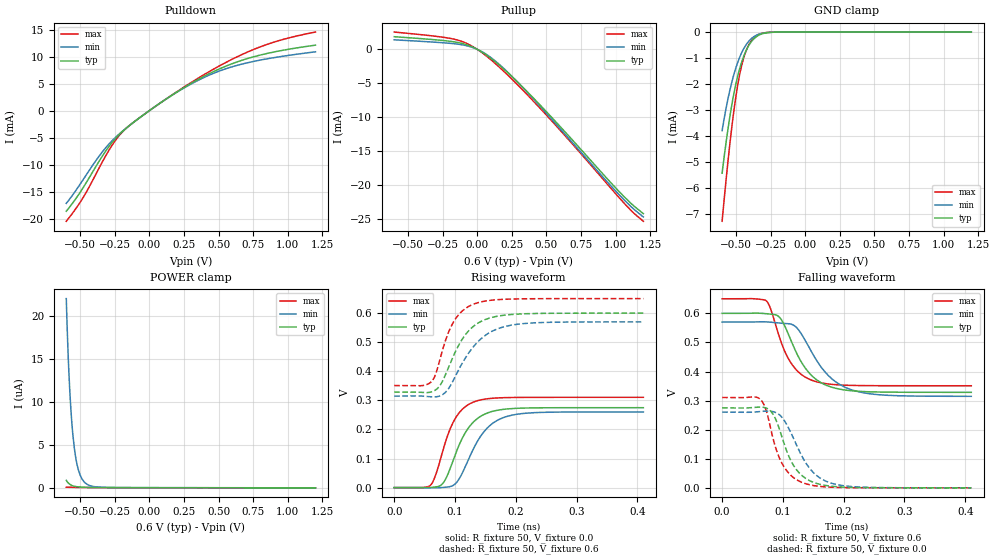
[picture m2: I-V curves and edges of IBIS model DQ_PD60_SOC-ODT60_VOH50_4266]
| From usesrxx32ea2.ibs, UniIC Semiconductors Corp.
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| DQ_PD60_SOC-ODT60_VOH50_4266
| (60 Ohm Pulldown, 60 Ohm System ODT Setting, VOH=VDDQ*0.50, 3200-4266Mbps)
[Model]   DQ_PD60_SOC-ODT60_VOH50_4266
Model_type   I/O
Vinl = 90.000mV
Vinh = 210.000mV
Vmeas = 150.000mV
Vref = 0.0mV
Cref = 0.0pF
Rref = 60.000Ohm
|   typ   min   max
|C_comp   0.834pF   0.784pF   0.884pF
C_comp_pullup   0.4170pF   0.3920pF   0.4420pF
C_comp_pulldown   0.4170pF   0.3920pF   0.4420pF
| Note: C_comp changes when the ODT circuit is enabled.
[Model Spec]
| Input threshold voltage corners
Vinl   0.0900V   0.0825V   0.1025V
Vinh   0.2100V   0.2025V   0.2225V
| Measurement voltage corners
Vmeas   0.1500V   0.1425V   0.1625V
| Timing spec test load voltage corners
Vref   0.0000V   0.0000V   0.0000V
| Dynamic Overshoot Parameters from LPDDR4_0P6 Specification
D_overshoot_ampl_h   0.30   NA   NA
D_overshoot_ampl_l   0.30   NA   NA
D_overshoot_area_h   0.1n   NA   NA
D_overshoot_area_l   0.1n   NA   NA
[Voltage Range]   0.6000V   0.5700V   0.6500V
[Pullup Reference]   0.6000V   0.5700V   0.6500V
| Junction Temperature (Ambient temp is 35C typ 95C min -40C max)
[Temperature Range]   50.0   110.0   -40.0
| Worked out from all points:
|   slope of the pulldown table from 0 to 0.09 V, typ, clamps not added: 55.7 ohm
|   slope of the pullup table from 0 to 0.09 V, typ, clamps not added: 75.7 ohm
|   GND clamp passes 1 mA (typ) near -0.45 V on its own axis
|   rising waveform, R_fixture 50, V_fixture 0.0: 20-80 % time 37.7ps typ, 42.2ps min, 32.6ps max; typ from 0 V to 0.275 V
|   falling waveform, R_fixture 50, V_fixture 0.6: 20-80 % time 43.5ps typ, 52.6ps min, 36.2ps max; typ from 0.6 V to 0.328 V
|   rising waveform, R_fixture 50, V_fixture 0.6: 20-80 % time 42.3ps typ, 50.4ps min, 32.9ps max; typ from 0.328 V to 0.6 V
|   falling waveform, R_fixture 50, V_fixture 0.0: 20-80 % time 34ps typ, 41.7ps min, 30.1ps max; typ from 0.275 V to 0 V
[Pulldown]
|   Voltage   I(typ)   I(min)   I(max)
-600mV    -18.62mA   -17.16mA   -20.48mA
-479.4mV  -14.31mA   -12.82mA   -16.14mA
-349.8mV  -8.833mA   -7.981mA   -9.987mA
-258mV    -5.562mA   -5.293mA   -5.98mA
-196.8mV  -3.935mA   -3.866mA   -4.014mA
-114mV    -2.168mA   -2.169mA   -2.139mA
211.8mV   3.655mA    3.602mA    3.717mA
490.8mV   7.545mA    7.184mA    8.063mA
658.2mV   9.231mA    8.542mA    10.26mA
825.6mV   10.44mA    9.472mA    12.04mA
1.006V    11.36mA    10.22mA    13.45mA
1.2V      12.12mA    10.89mA    14.55mA
[GND Clamp]
|   Voltage   I(typ)   I(min)   I(max)
-600mV    -5.439mA   -3.802mA   -7.294mA
-565.8mV  -4.041mA   -2.789mA   -5.405mA
-537mV    -3.03mA    -2.086mA   -3.984mA
-510mV    -2.24mA    -1.545mA   -2.838mA
-483mV    -1.605mA   -1.108mA   -1.913mA
-457.8mV  -1.142mA   -788.2uA   -1.267mA
-427.2mV  -721.7uA   -495.2uA   -731.4uA
-396.6mV  -430.3uA   -293.3uA   -396.7uA
-358.8mV  -204.8uA   -141.3uA   -167.1uA
-301.2mV  -53.74uA   -39.26uA   -35.2uA
-218.4mV  -5.224uA   -4.672uA   -2.177uA
1.2V      0A         0A         0A
[Pullup]
|   Voltage   I(typ)   I(min)   I(max)
-600mV    1.862mA    1.404mA    2.549mA
-297.6mV  1.399mA    1.043mA    1.916mA
-146.4mV  1.034mA    781.4uA    1.389mA
-27.6mV   277.3uA    226.3uA    350.3uA
28.2mV    -327uA     -281uA     -397uA
85.8mV    -1.126mA   -1.018mA   -1.31mA
201mV     -3.083mA   -2.993mA   -3.411mA
357.6mV   -6.168mA   -6.244mA   -6.596mA
615mV     -11.72mA   -12.05mA   -12.27mA
1.009V    -20.59mA   -21.06mA   -21.46mA
1.106V    -22.59mA   -23.05mA   -23.62mA
1.2V      -24.19mA   -24.67mA   -25.31mA
[POWER Clamp]
|   Voltage   I(typ)   I(min)   I(max)
-600mV    870.6nA    21.97uA    72.65nA
-589.2mV  630.1nA    16.59uA    68.66nA
-583.8mV  538.6nA    14.38uA    66.96nA
-576.6mV  440.3nA    11.88uA    64.76nA
-565.8mV  328nA      8.878uA    61.57nA
-551.4mV  228.5nA    6.002uA    57.54nA
-533.4mV  154.5nA    3.671uA    52.81nA
-513.6mV  108.8nA    2.145uA    47.98nA
-492mV    81.81nA    1.201uA    43.12nA
-454.2mV  59.07nA    454.9nA    35.59nA
-304.8mV  31.78nA    52.14nA    15.54nA
1.2V      0A         0A         0A
[Ramp]
|   typ   min   max
| 20% - 80%
dV/dt_r   164.90m/37.66p   156.14m/42.15p   186.33m/32.58p
dV/dt_f   162.96m/43.53p   153.17m/52.61p   179.39m/36.16p
| 25% - 75%
|dV/dt_r   137.42m/29.82p   130.12m/33.41p   155.27m/25.73p
|dV/dt_f   135.80m/34.45p   127.64m/41.67p   149.49m/28.54p
R_load = 50
[Rising Waveform]
R_fixture = 50
V_fixture = 0.0
|   Time   V(typ)   V(min)   V(max)
0s        128.2uV    112.5uV    62.99uV
60ps      528.7uV    -338.6uV   9.002mV
68ps      2.334mV    -607.4uV   42.24mV
80ps      14.5mV     625uV      126.7mV
98ps      99.64mV    8.971mV    228.6mV
114ps     178mV      58.56mV    273.2mV
132ps     229mV      140.4mV    295.6mV
159ps     260.7mV    216.3mV    306.9mV
196ps     272.2mV    250.2mV    310.1mV
410ps     275mV      260.3mV    310.6mV
[Falling Waveform]
R_fixture   = 50
V_fixture   = 0.6
V_fixture_min = 0.57
V_fixture_max = 0.65
|   Time   V(typ)   V(min)   V(max)
0s        600mV      570mV      650mV
73ps      598.8mV    570.6mV    642.3mV
80ps      597.2mV    569.6mV    614.3mV
94ps      587.4mV    566.5mV    519.9mV
110ps     523.5mV    564.2mV    440.6mV
126ps     448.9mV    542.6mV    397.5mV
149ps     382.7mV    460.7mV    368.8mV
182ps     345mV      372.4mV    355.5mV
223ps     332.1mV    331.1mV    351.8mV
410ps     328.4mV    314.7mV    351mV
[Rising Waveform]
R_fixture   = 50
V_fixture   = 0.6
V_fixture_min = 0.57
V_fixture_max = 0.65
|   Time   V(typ)   V(min)   V(max)
0s        328.4mV    314.6mV    351mV
61ps      329mV      312.3mV    363.9mV
68ps      335.8mV    312.2mV    389.1mV
77ps      356.7mV    316.9mV    454.5mV
96ps      446.2mV    363.9mV    563.7mV
114ps     516.8mV    435.2mV    611mV
132ps     557.4mV    488.8mV    632.1mV
161ps     585.5mV    537.8mV    644.7mV
201ps     596.6mV    561.4mV    649mV
410ps     600mV      570mV      650mV
[Falling Waveform]
R_fixture = 50
V_fixture = 0.0
|   Time   V(typ)   V(min)   V(max)
0s        275mV      260.4mV    310.6mV
64ps      277.7mV    262.7mV    302mV
73ps      274.1mV    263.9mV    263.2mV
82ps      258.5mV    262.8mV    184.7mV
97ps      184.6mV    245.9mV    90.47mV
113ps     94.29mV    190.2mV    43.21mV
132ps     41.15mV    106mV      18.21mV
157ps     14.23mV    39.92mV    5.926mV
192ps     3.451mV    9.939mV    1.328mV
410ps     188.9uV    197.1uV    88.71uV
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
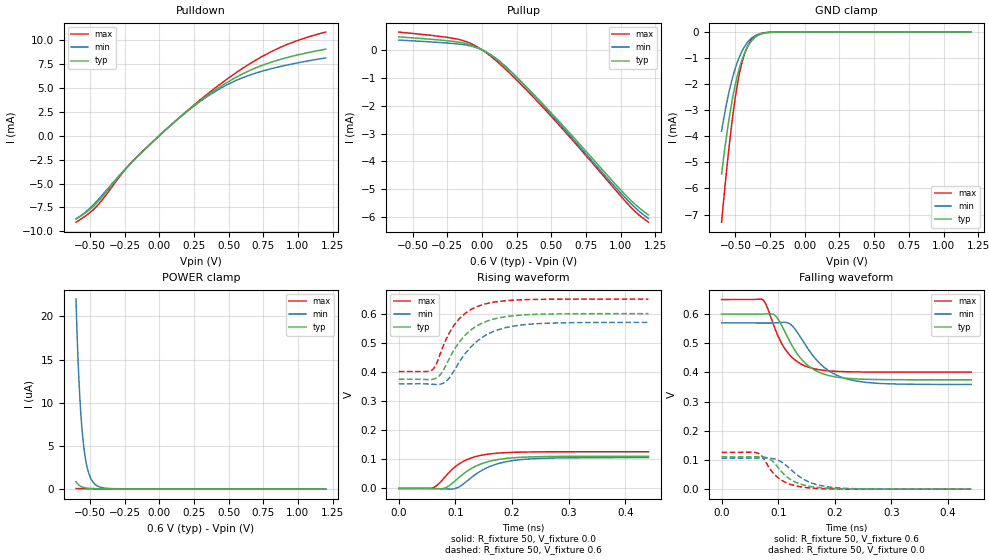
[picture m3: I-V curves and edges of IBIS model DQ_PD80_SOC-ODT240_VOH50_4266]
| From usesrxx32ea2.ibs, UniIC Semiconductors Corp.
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| DQ_PD80_SOC-ODT240_VOH50_4266
| (80 Ohm Pulldown, 240 Ohm System ODT Setting, VOH=VDDQ*0.50, 3200-4266Mbps)
[Model]   DQ_PD80_SOC-ODT240_VOH50_4266
Model_type   I/O
Vinl = 90.000mV
Vinh = 210.000mV
Vmeas = 150.000mV
Vref = 0.0mV
Cref = 0.0pF
Rref = 240.000Ohm
|   typ   min   max
|C_comp   0.834pF   0.784pF   0.884pF
C_comp_pullup   0.4170pF   0.3920pF   0.4420pF
C_comp_pulldown   0.4170pF   0.3920pF   0.4420pF
| Note: C_comp changes when the ODT circuit is enabled.
[Model Spec]
| Input threshold voltage corners
Vinl   0.0900V   0.0825V   0.1025V
Vinh   0.2100V   0.2025V   0.2225V
| Measurement voltage corners
Vmeas   0.1500V   0.1425V   0.1625V
| Timing spec test load voltage corners
Vref   0.0000V   0.0000V   0.0000V
| Dynamic Overshoot Parameters from LPDDR4_0P6 Specification
D_overshoot_ampl_h   0.30   NA   NA
D_overshoot_ampl_l   0.30   NA   NA
D_overshoot_area_h   0.1n   NA   NA
D_overshoot_area_l   0.1n   NA   NA
[Voltage Range]   0.6000V   0.5700V   0.6500V
[Pullup Reference]   0.6000V   0.5700V   0.6500V
| Junction Temperature (Ambient temp is 35C typ 95C min -40C max)
[Temperature Range]   50.0   110.0   -40.0
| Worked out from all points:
|   slope of the pulldown table from 0 to 0.09 V, typ, clamps not added: 75.6 ohm
|   slope of the pullup table from 0 to 0.09 V, typ, clamps not added: 306 ohm
|   GND clamp passes 1 mA (typ) near -0.45 V on its own axis
|   rising waveform, R_fixture 50, V_fixture 0.0: 20-80 % time 54.3ps typ, 56.9ps min, 47.6ps max; typ from 0 V to 0.11 V
|   falling waveform, R_fixture 50, V_fixture 0.6: 20-80 % time 47.3ps typ, 56.1ps min, 39.6ps max; typ from 0.6 V to 0.375 V
|   rising waveform, R_fixture 50, V_fixture 0.6: 20-80 % time 53ps typ, 58.6ps min, 45.8ps max; typ from 0.375 V to 0.6 V
|   falling waveform, R_fixture 50, V_fixture 0.0: 20-80 % time 38.7ps typ, 46.9ps min, 35.2ps max; typ from 0.111 V to 0 V
[Pulldown]
|   Voltage   I(typ)   I(min)   I(max)
-600mV    -8.692mA   -8.695mA   -9.046mA
-513.6mV  -7.87mA    -7.758mA   -8.201mA
-447mV    -6.974mA   -6.797mA   -7.322mA
-241.8mV  -3.459mA   -3.444mA   -3.485mA
-135.6mV  -1.874mA   -1.886mA   -1.844mA
130.8mV   1.709mA    1.698mA    1.715mA
247.8mV   3.122mA    3.073mA    3.178mA
370.2mV   4.454mA    4.329mA    4.624mA
577.2mV   6.292mA    5.923mA    6.818mA
800.4mV   7.658mA    6.983mA    8.741mA
967.8mV   8.348mA    7.534mA    9.805mA
1.2V      9.057mA    8.141mA    10.84mA
[GND Clamp]
|   Voltage   I(typ)   I(min)   I(max)
-600mV    -5.439mA   -3.802mA   -7.294mA
-565.8mV  -4.041mA   -2.788mA   -5.405mA
-535.2mV  -2.974mA   -2.045mA   -3.902mA
-508.2mV  -2.194mA   -1.512mA   -2.769mA
-483mV    -1.606mA   -1.109mA   -1.914mA
-456mV    -1.113mA   -769.6uA   -1.229mA
-427.2mV  -720.5uA   -496.7uA   -731.4uA
-398.4mV  -442.8uA   -303.7uA   -412uA
-360.6mV  -213.6uA   -146.5uA   -174.9uA
-303mV    -56.19uA   -40.92uA   -37.12uA
-202.2mV  -3.152uA   -2.988uA   -1.162uA
1.2V      0A         0A         0A
[Pullup]
|   Voltage   I(typ)   I(min)   I(max)
-600mV    465uA      350.7uA    636.6uA
-286.8mV  344.5uA    256.9uA    471.4uA
-139.2mV  251.1uA    190.4uA    336.1uA
-25.8mV   64.71uA    52.97uA    81.67uA
26.4mV    -75.59uA   -64.92uA   -91.9uA
82.2mV    -265.3uA   -239.4uA   -309.4uA
186.6mV   -696.9uA   -671.7uA   -775.1uA
307.2mV   -1.269mA   -1.271mA   -1.369mA
591.6mV   -2.763mA   -2.837mA   -2.897mA
978.6mV   -4.91mA    -5.02mA    -5.117mA
1.106V    -5.551mA   -5.669mA   -5.807mA
1.2V      -5.919mA   -6.049mA   -6.179mA
[POWER Clamp]
|   Voltage   I(typ)   I(min)   I(max)
-600mV    870.6nA    22uA       72.65nA
-589.2mV  630.2nA    16.59uA    68.66nA
-583.8mV  538.6nA    14.38uA    66.97nA
-576.6mV  439.2nA    11.87uA    64.76nA
-562.2mV  298.4nA    8.05uA     60.55nA
-547.8mV  211nA      5.442uA    56.57nA
-529.8mV  144.6nA    3.33uA     51.9nA
-506.4mV  97.9nA     1.762uA    46.31nA
-484.8mV  75.65nA    991.9nA    41.6nA
-450.6mV  57.67nA    416.8nA    34.94nA
-303mV    31.59nA    51.65nA    15.37nA
1.2V      0A         0A         0A
[Ramp]
|   typ   min   max
| 20% - 80%
dV/dt_r   66.28m/54.26p   63.59m/56.93p   75.63m/47.62p
dV/dt_f   135.04m/47.27p   126.64m/56.05p   149.25m/39.63p
| 25% - 75%
|dV/dt_r   55.23m/43.09p   52.99m/45.13p   63.03m/37.68p
|dV/dt_f   112.53m/37.46p   105.54m/44.39p   124.38m/31.36p
R_load = 50
[Rising Waveform]
R_fixture = 50
V_fixture = 0.0
|   Time   V(typ)   V(min)   V(max)
0s        20.21uV    7.273uV    14.24uV
58ps      -516.5uV   122.6uV    588.5uV
80ps      847uV      -1.599mV   36.07mV
98ps      23.63mV    -986uV     71.81mV
112ps     47.06mV    12.57mV    90.75mV
133ps     73.78mV    44.73mV    107.9mV
156ps     91.12mV    71.39mV    117.4mV
190ps     103.2mV    91.95mV    123.1mV
236ps     108.6mV    102mV      125.4mV
441ps     110.5mV    106mV      126.1mV
[Falling Waveform]
R_fixture   = 50
V_fixture   = 0.6
V_fixture_min = 0.57
V_fixture_max = 0.65
|   Time   V(typ)   V(min)   V(max)
0s        600mV      570mV      650mV
73ps      600.5mV    569.9mV    648.8mV
80ps      601.3mV    569.6mV    626.3mV
94ps      596.2mV    570.1mV    551.8mV
112ps     538.8mV    571.9mV    480.7mV
128ps     480.3mV    553mV      445.3mV
156ps     418.7mV    471.6mV    416.5mV
190ps     389.3mV    405mV      405.5mV
236ps     378.1mV    371.3mV    402mV
441ps     374.9mV    358.9mV    401.2mV
[Rising Waveform]
R_fixture   = 50
V_fixture   = 0.6
V_fixture_min = 0.57
V_fixture_max = 0.65
|   Time   V(typ)   V(min)   V(max)
0s        374.9mV    358.8mV    401.2mV
60ps      374.4mV    357mV      408.6mV
72ps      387.4mV    357.5mV    455.9mV
82ps      418.2mV    365.4mV    505.4mV
100ps     483.1mV    412.2mV    566.6mV
123ps     536.6mV    476.4mV    608.8mV
148ps     568.1mV    519.3mV    630.8mV
180ps     586.7mV    547.4mV    642.7mV
225ps     596.1mV    562.7mV    648.1mV
441ps     600mV      570mV      650mV
[Falling Waveform]
R_fixture = 50
V_fixture = 0.0
|   Time   V(typ)   V(min)   V(max)
0s        110.6mV    106.1mV    126.1mV
61ps      111.4mV    106.6mV    125.3mV
71ps      111.2mV    107mV      113.6mV
80ps      108mV      106.7mV    86.26mV
105ps     61.84mV    94.18mV    31.83mV
121ps     34.15mV    69.65mV    16.87mV
143ps     15.17mV    36.08mV    7.033mV
172ps     5.248mV    13.57mV    2.23mV
213ps     1.226mV    3.428mV    468.6uV
441ps     86.87uV    93.26uV    32.34uV
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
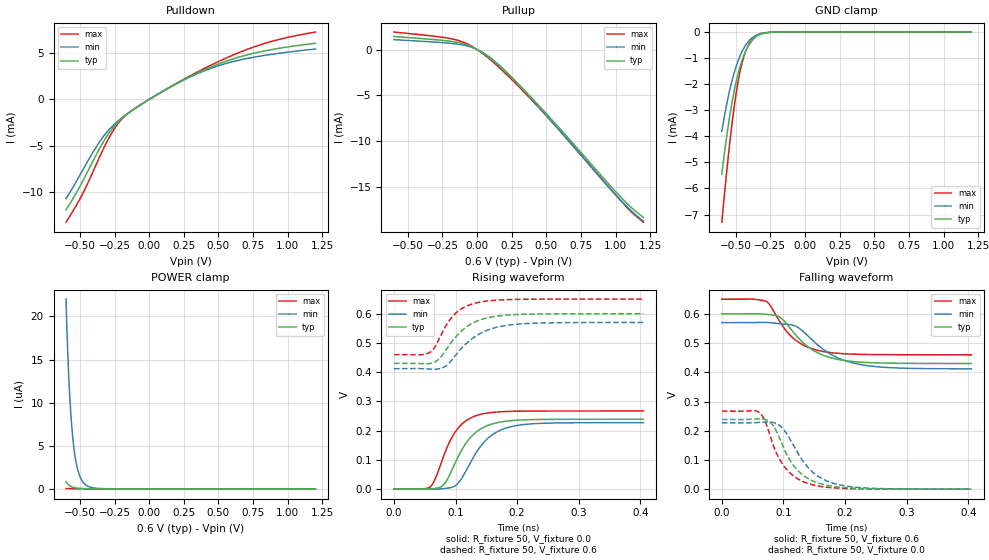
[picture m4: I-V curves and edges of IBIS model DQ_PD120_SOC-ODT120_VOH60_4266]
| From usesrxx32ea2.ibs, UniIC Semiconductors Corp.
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| DQ_PD120_SOC-ODT120_VOH60_4266
| (120 Ohm Pulldown, 120 Ohm System ODT Setting, VOH=VDDQ*0.60, 3200-4266Mbps)
[Model]   DQ_PD120_SOC-ODT120_VOH60_4266
Model_type   I/O
Vinl = 120.000mV
Vinh = 240.000mV
Vmeas = 180.000mV
Vref = 0.0mV
Cref = 0.0pF
Rref = 120.000Ohm
|   typ   min   max
|C_comp   0.834pF   0.784pF   0.884pF
C_comp_pullup   0.4170pF   0.3920pF   0.4420pF
C_comp_pulldown   0.4170pF   0.3920pF   0.4420pF
| Note: C_comp changes when the ODT circuit is enabled.
[Model Spec]
| Input threshold voltage corners
Vinl   0.1200V   0.1110V   0.1350V
Vinh   0.2400V   0.2310V   0.2550V
| Measurement voltage corners
Vmeas   0.1800V   0.1710V   0.1950V
| Timing spec test load voltage corners
Vref   0.0000V   0.0000V   0.0000V
| Dynamic Overshoot Parameters from LPDDR4_0P6 Specification
D_overshoot_ampl_h   0.30   NA   NA
D_overshoot_ampl_l   0.30   NA   NA
D_overshoot_area_h   0.1n   NA   NA
D_overshoot_area_l   0.1n   NA   NA
[Voltage Range]   0.6000V   0.5700V   0.6500V
[Pullup Reference]   0.6000V   0.5700V   0.6500V
| Junction Temperature (Ambient temp is 35C typ 95C min -40C max)
[Temperature Range]   50.0   110.0   -40.0
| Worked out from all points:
|   slope of the pulldown table from 0 to 0.09 V, typ, clamps not added: 111 ohm
|   slope of the pullup table from 0 to 0.09 V, typ, clamps not added: 98.8 ohm
|   GND clamp passes 1 mA (typ) near -0.45 V on its own axis
|   rising waveform, R_fixture 50, V_fixture 0.0: 20-80 % time 41ps typ, 44.6ps min, 35.8ps max; typ from 0 V to 0.239 V
|   falling waveform, R_fixture 50, V_fixture 0.6: 20-80 % time 53ps typ, 62.4ps min, 44.7ps max; typ from 0.6 V to 0.43 V
|   rising waveform, R_fixture 50, V_fixture 0.6: 20-80 % time 45.7ps typ, 51ps min, 36.8ps max; typ from 0.43 V to 0.6 V
|   falling waveform, R_fixture 50, V_fixture 0.0: 20-80 % time 41.6ps typ, 47.6ps min, 38ps max; typ from 0.239 V to 0 V
[Pulldown]
|   Voltage   I(typ)   I(min)   I(max)
-600mV    -11.92mA   -10.72mA   -13.26mA
-483mV    -8.922mA   -7.73mA    -10.28mA
-394.8mV  -6.348mA   -5.442mA   -7.454mA
-335.4mV  -4.715mA   -4.111mA   -5.505mA
-285mV    -3.534mA   -3.192mA   -4.02mA
-238.2mV  -2.657mA   -2.498mA   -2.886mA
-142.8mV  -1.403mA   -1.39mA    -1.395mA
175.8mV   1.532mA    1.515mA    1.549mA
462mV     3.597mA    3.444mA    3.816mA
631.2mV   4.493mA    4.178mA    4.953mA
823.8mV   5.21mA     4.731mA    6.002mA
1.2V      6.059mA    5.442mA    7.269mA
[GND Clamp]
|   Voltage   I(typ)   I(min)   I(max)
-600mV    -5.44mA    -3.802mA   -7.294mA
-564mV    -3.973mA   -2.741mA   -5.311mA
-533.4mV  -2.917mA   -2.006mA   -3.82mA
-506.4mV  -2.15mA    -1.48mA    -2.701mA
-481.2mV  -1.57mA    -1.083mA   -1.859mA
-456mV    -1.112mA   -767.7uA   -1.229mA
-427.2mV  -721.8uA   -495.2uA   -731.5uA
-394.8mV  -414.6uA   -283.6uA   -381.9uA
-360.6mV  -213.8uA   -146.4uA   -174.6uA
-303mV    -56.36uA   -40.77uA   -36.95uA
-196.8mV  -2.673uA   -2.578uA   -928.3nA
1.2V      0A         0A         0A
[Pullup]
|   Voltage   I(typ)   I(min)   I(max)
-600mV    1.424mA    1.081mA    1.912mA
-285mV    1.057mA    794.8uA    1.413mA
-142.8mV  785.3uA    600.3uA    1.027mA
-79.8mV   535.2uA    425.4uA    679uA
-24mV     186.8uA    154.7uA    230.2uA
80.4mV    -800uA     -726.5uA   -913.6uA
206.4mV   -2.437mA   -2.382mA   -2.635mA
357.6mV   -4.719mA   -4.789mA   -4.942mA
618.6mV   -9.022mA   -9.285mA   -9.253mA
1.016V    -15.83mA   -16.18mA   -16.2mA
1.117V    -17.35mA   -17.73mA   -17.84mA
1.2V      -18.38mA   -18.78mA   -18.91mA
[POWER Clamp]
|   Voltage   I(typ)   I(min)   I(max)
-600mV    870.6nA    21.99uA    72.65nA
-589.2mV  630.1nA    16.59uA    68.66nA
-583.8mV  538.5nA    14.38uA    66.96nA
-576.6mV  439nA      11.87uA    64.76nA
-564mV    312.8nA    8.452uA    61.06nA
-547.8mV  210.6nA    5.441uA    56.57nA
-529.8mV  145.1nA    3.331uA    51.9nA
-510mV    103.4nA    1.947uA    47.14nA
-486.6mV  77.28nA    1.041uA    41.97nA
-457.8mV  60.48nA    497.8nA    36.26nA
-312mV    32.55nA    54.2nA     16.21nA
1.2V      0A         0A         0A
[Ramp]
|   typ   min   max
| 20% - 80%
dV/dt_r   143.18m/40.97p   136.20m/44.63p   160.26m/35.75p
dV/dt_f   101.96m/52.99p   94.91m/62.42p   114.04m/44.74p
| 25% - 75%
|dV/dt_r   119.31m/32.44p   113.50m/35.33p   133.55m/28.24p
|dV/dt_f   84.97m/41.97p   79.09m/49.44p   95.03m/35.34p
R_load = 50
[Rising Waveform]
R_fixture = 50
V_fixture = 0.0
|   Time   V(typ)   V(min)   V(max)
0s        136.2uV    126.7uV    64.4uV
58ps      299.6uV    -171.3uV   6.223mV
66ps      1.907mV    -302.2uV   30.25mV
78ps      9.544mV    982.8uV    96.96mV
103ps     105.4mV    17.61mV    205.4mV
118ps     160mV      66.52mV    235.3mV
135ps     197.3mV    129.6mV    252.3mV
162ps     224.4mV    189mV      262.8mV
199ps     235.5mV    217.3mV    266.4mV
405ps     238.8mV    227.1mV    267.2mV
[Falling Waveform]
R_fixture   = 50
V_fixture   = 0.6
V_fixture_min = 0.57
V_fixture_max = 0.65
|   Time   V(typ)   V(min)   V(max)
0s        600mV      570mV      650mV
72ps      598.5mV    570.7mV    642.9mV
79ps      596.7mV    569.8mV    627.4mV
94ps      588.8mV    566.1mV    573.5mV
114ps     542.8mV    562.1mV    520.3mV
135ps     495.5mV    534.1mV    490.2mV
159ps     463.2mV    487.6mV    473.5mV
192ps     442.6mV    446.1mV    464.4mV
233ps     433.7mV    423.8mV    461mV
405ps     430.1mV    411.8mV    459.9mV
[Rising Waveform]
R_fixture   = 50
V_fixture   = 0.6
V_fixture_min = 0.57
V_fixture_max = 0.65
|   Time   V(typ)   V(min)   V(max)
0s        430mV      411.7mV    459.9mV
59ps      429.7mV    410.1mV    468.5mV
67ps      435.5mV    409.6mV    487.5mV
80ps      462.3mV    415.7mV    542.3mV
97ps      512mV      449.2mV    594.6mV
115ps     550.2mV    493.2mV    622.9mV
135ps     574.9mV    526mV      637.6mV
164ps     590.7mV    552mV      645.9mV
203ps     597.5mV    564.7mV    649mV
405ps     600mV      570mV      650mV
[Falling Waveform]
R_fixture = 50
V_fixture = 0.0
|   Time   V(typ)   V(min)   V(max)
0s        238.8mV    227.2mV    267.2mV
58ps      241mV      228.1mV    266mV
76ps      233.1mV    230mV      198.8mV
88ps      201mV      225.1mV    126.6mV
102ps     133.8mV    200.1mV    75.82mV
118ps     76.87mV    143.4mV    42.71mV
141ps     35.45mV    71.73mV    18.79mV
169ps     13.98mV    29.52mV    6.968mV
209ps     3.866mV    8.6mV      1.778mV
405ps     223.3uV    241.8uV    97.17uV
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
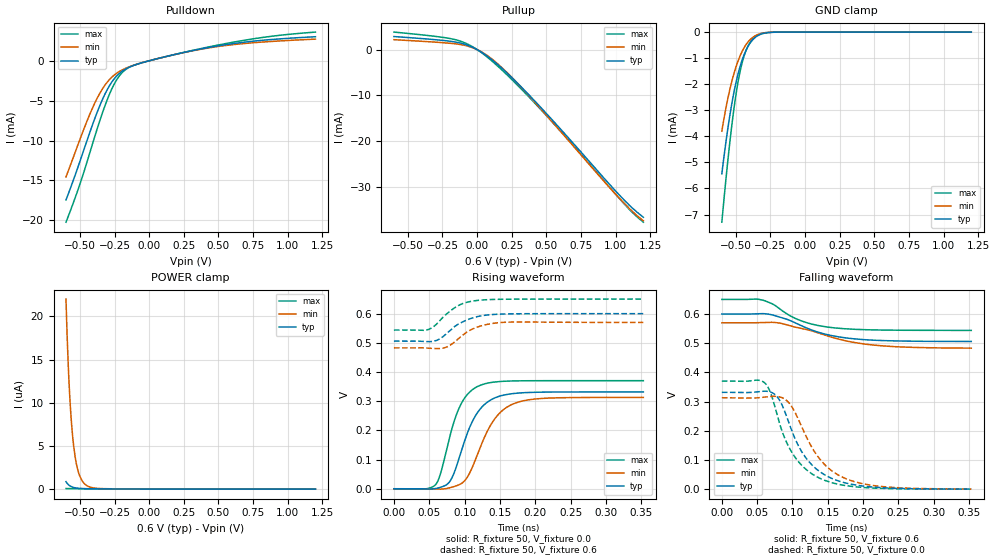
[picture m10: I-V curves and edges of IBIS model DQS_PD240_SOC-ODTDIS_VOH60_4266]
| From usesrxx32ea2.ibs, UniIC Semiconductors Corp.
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| DQS_PD240_SOC-ODTDIS_VOH60_4266
| (240 Ohm Pulldown, SOC ODT disabled setting, VOH=VDDQ*0.60 cal. point, 3200-4266Mbps)
[Model]   DQS_PD240_SOC-ODTDIS_VOH60_4266
Model_type   I/O
Vinl = 120.000mV
Vinh = 240.000mV
Vmeas = 180.000mV
Vref = 0.0mV
Cref = 0.0pF
|   typ   min   max
|C_comp   0.849pF   0.799pF   0.899pF
C_comp_pullup   0.4245pF   0.3995pF   0.4495pF
C_comp_pulldown   0.4245pF   0.3995pF   0.4495pF
| Note: C_comp changes when the ODT circuit is enabled.
[Model Spec]
| Input threshold voltage corners
Vinl   0.1200V   0.1110V   0.1350V
Vinh   0.2400V   0.2310V   0.2550V
| Measurement voltage corners
Vmeas   0.1800V   0.1710V   0.1950V
| Timing spec test load voltage corners
Vref   0.0000V   0.0000V   0.0000V
| Dynamic Overshoot Parameters from LPDDR4_0P6 Specification
D_overshoot_ampl_h   0.30   NA   NA
D_overshoot_ampl_l   0.30   NA   NA
D_overshoot_area_h   0.1n   NA   NA
D_overshoot_area_l   0.1n   NA   NA
[Voltage Range]   0.6000V   0.5700V   0.6500V
[Pullup Reference]   0.6000V   0.5700V   0.6500V
| Junction Temperature (Ambient temp is 35C typ 95C min -40C max)
[Temperature Range]   50.0   110.0   -40.0
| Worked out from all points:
|   slope of the pulldown table from 0 to 0.09 V, typ, clamps not added: 227 ohm
|   slope of the pullup table from 0 to 0.09 V, typ, clamps not added: 49.6 ohm
|   GND clamp passes 1 mA (typ) near -0.45 V on its own axis
|   rising waveform, R_fixture 50, V_fixture 0.0: 20-80 % time 32.5ps typ, 37.3ps min, 27.8ps max; typ from 0 V to 0.332 V
|   falling waveform, R_fixture 50, V_fixture 0.6: 20-80 % time 65.3ps typ, 83.8ps min, 52.1ps max; typ from 0.6 V to 0.506 V
|   rising waveform, R_fixture 50, V_fixture 0.6: 20-80 % time 35ps typ, 31.9ps min, 31.3ps max; typ from 0.506 V to 0.6 V
|   falling waveform, R_fixture 50, V_fixture 0.0: 20-80 % time 45.9ps typ, 49.5ps min, 42.7ps max; typ from 0.332 V to 0.001 V
[Pulldown]
|   Voltage   I(typ)   I(min)   I(max)
-600mV    -17.44mA   -14.55mA   -20.23mA
-497.4mV  -12.5mA    -9.763mA   -15.35mA
-427.2mV  -8.932mA   -6.662mA   -11.47mA
-362.4mV  -5.897mA   -4.287mA   -7.851mA
-315.6mV  -4.065mA   -2.984mA   -5.487mA
-261.6mV  -2.481mA   -1.937mA   -3.253mA
-214.8mV  -1.585mA   -1.343mA   -1.899mA
-171.6mV  -1.056mA   -960.5uA   -1.137mA
-34.8mV   -172.9uA   -171.5uA   -162.9uA
444mV     1.699mA    1.642mA    1.777mA
836.4mV   2.588mA    2.36mA     2.955mA
1.2V      3.005mA    2.705mA    3.586mA
[GND Clamp]
|   Voltage   I(typ)   I(min)   I(max)
-600mV    -5.44mA    -3.803mA   -7.294mA
-565.8mV  -4.042mA   -2.789mA   -5.405mA
-535.2mV  -2.973mA   -2.046mA   -3.902mA
-508.2mV  -2.193mA   -1.512mA   -2.769mA
-483mV    -1.605mA   -1.109mA   -1.912mA
-456mV    -1.113mA   -768.5uA   -1.229mA
-425.4mV  -700.6uA   -481.5uA   -707.1uA
-393mV    -401.5uA   -274.5uA   -367.8uA
-357mV    -196.7uA   -135.9uA   -160.3uA
-292.2mV  -42.68uA   -31.94uA   -26.87uA
-198.6mV  -2.811uA   -2.711uA   -998.1nA
1.2V      0A         0A         0A
[Pullup]
|   Voltage   I(typ)   I(min)   I(max)
-600mV    2.847mA    2.16mA     3.822mA
-270.6mV  2.072mA    1.558mA    2.767mA
-141mV    1.559mA    1.192mA    2.035mA
-25.8mV   399uA      330uA      491.6uA
30mV      -534.8uA   -464.3uA   -632.5uA
82.2mV    -1.634mA   -1.486mA   -1.864mA
215.4mV   -5.103mA   -5.003mA   -5.503mA
406.2mV   -10.92mA   -11.14mA   -11.37mA
640.2mV   -18.66mA   -19.19mA   -19.13mA
991.2mV   -30.64mA   -31.33mA   -31.33mA
1.106V    -34.24mA   -34.96mA   -35.17mA
1.2V      -36.67mA   -37.43mA   -37.73mA
[POWER Clamp]
|   Voltage   I(typ)   I(min)   I(max)
-600mV    870.6nA    21.99uA    72.65nA
-594.6mV  739.5nA    19.12uA    70.4nA
-589.2mV  630.1nA    16.59uA    68.66nA
-578.4mV  462nA      12.46uA    65.31nA
-565.8mV  328.2nA    8.879uA    61.57nA
-549.6mV  219.3nA    5.716uA    57.05nA
-533.4mV  154.4nA    3.681uA    52.81nA
-510mV    103.1nA    1.947uA    47.14nA
-483mV    74.3nA     947.5nA    41.22nA
-454.2mV  58.97nA    457.8nA    35.6nA
-304.8mV  31.77nA    52.11nA    15.53nA
1.2V      0A         0A         0A
[Ramp]
|   typ   min   max
| 20% - 80%
dV/dt_r   198.94m/32.54p   187.71m/37.29p   222.23m/27.81p
dV/dt_f   56.37m/65.31p   52.06m/83.78p   63.59m/52.14p
| 25% - 75%
|dV/dt_r   165.78m/25.67p   156.42m/29.48p   185.19m/22.04p
|dV/dt_f   46.97m/51.20p   43.38m/64.61p   52.99m/41.11p
R_load = 50
[Rising Waveform]
R_fixture = 50
V_fixture = 0.0
|   Time   V(typ)   V(min)   V(max)
0s        347.2uV    338.8uV    157.3uV
59ps      1.034mV    -888.5uV   14.43mV
66ps      5.385mV    -1.011mV   52.64mV
79ps      24.85mV    3.505mV    178.1mV
93ps      110.8mV    14.91mV    280.7mV
106ps     203.6mV    48.74mV    328.7mV
122ps     273.4mV    141mV      354.5mV
145ps     313.7mV    247.1mV    366.6mV
176ps     328.1mV    297.2mV    369.9mV
353ps     331.9mV    313.2mV    370.5mV
[Falling Waveform]
R_fixture   = 50
V_fixture   = 0.6
V_fixture_min = 0.57
V_fixture_max = 0.65
|   Time   V(typ)   V(min)   V(max)
0s        600mV      570mV      650mV
58ps      601.4mV    571.2mV    647.6mV
72ps      596.7mV    571.6mV    634.3mV
81ps      590mV      569.4mV    619.5mV
109ps     564mV      552.5mV    579.8mV
129ps     543.7mV    541.1mV    564.6mV
152ps     527.9mV    523.2mV    554.7mV
186ps     515.4mV    503.2mV    548mV
223ps     509.6mV    491.9mV    545.3mV
353ps     506.1mV    483.2mV    544mV
[Rising Waveform]
R_fixture   = 50
V_fixture   = 0.6
V_fixture_min = 0.57
V_fixture_max = 0.65
|   Time   V(typ)   V(min)   V(max)
0s        505.9mV    482.8mV    544mV
48ps      504.2mV    482mV      545.2mV
60ps      508.1mV    480.3mV    563.5mV
71ps      524.3mV    482.8mV    591.6mV
80ps      543.9mV    492.7mV    609.6mV
93ps      566.7mV    517.6mV    630mV
116ps     588.8mV    552.4mV    644.8mV
138ps     596.8mV    565.9mV    648.5mV
161ps     599.2mV    570.9mV    649.6mV
353ps     600mV      570mV      650mV
[Falling Waveform]
R_fixture = 50
V_fixture = 0.0
|   Time   V(typ)   V(min)   V(max)
0s        332mV      313.3mV    370.6mV
57ps      335.5mV    314.5mV    370.1mV
66ps      334.7mV    317.1mV    346.5mV
75ps      324.7mV    318.3mV    283.4mV
87ps      278.8mV    311.6mV    187.2mV
101ps     188.1mV    274.9mV    118.9mV
118ps     110.5mV    187.7mV    70.33mV
140ps     57.9mV     99.2mV     36.06mV
203ps     9.928mV    17.19mV    5.473mV
353ps     551uV      714.7uV    247.2uV
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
